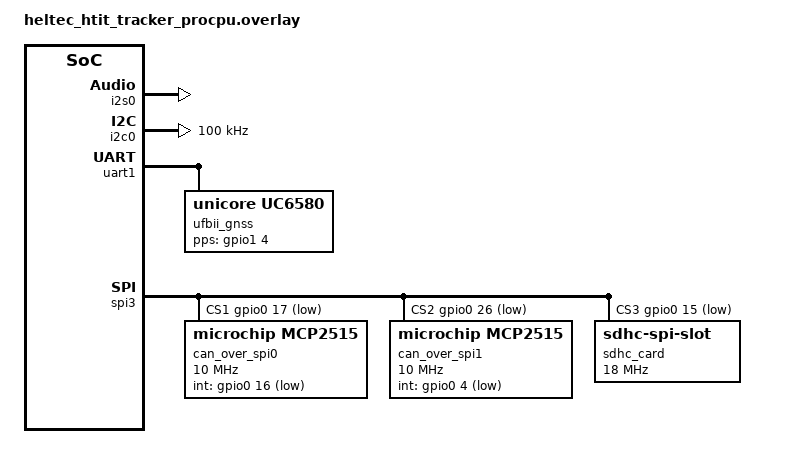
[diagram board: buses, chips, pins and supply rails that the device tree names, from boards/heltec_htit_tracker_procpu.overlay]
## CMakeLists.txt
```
cmake_minimum_required(VERSION 3.20.0)
find_package(Zephyr REQUIRED HINTS $ENV{ZEPHYR_BASE})

project(hyundai-remote)

target_sources(app PRIVATE 
    src/main.c
    src/built-in-test.c
    src/roles.c
    src/sys/storage.c
    src/sys/audio.c
    src/sys/nrvc2_can.c
    src/sys/comms.c
)

target_include_directories(app PRIVATE
    nrvc2_security/include
    ../include/nrvc2
)

target_link_libraries(app PRIVATE 
    nrvc2_security
)
```

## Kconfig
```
config DEVICE_ROLE
    int "DEVICE_ROLE | 1: FOB, 2: TRC"
    range 1 2
    default 1 if CONFIG_BOARD_HELTEC_WIFI_LORA32_v3
    default 2 if CONFIG_BOARD_HELTEC_HTIT_TRACKER
    help
        Set device role, 1: fob-commander-transmitter, 2: tracker-controller-transponder

menu "Installed Devices"
    config EN_GPIO_LED0
        bool "LED0 Installed"
        default y
        help
            Enable if LED 0 is installed.

    config EN_GPIO_SW0
        bool "SW0 Installed"
        default y
        help
            Enable if Switch 0 is installed.

    config EN_DEV_LORA
        bool "LORA Installed"
        default y
        help
            Enable if LoRa transmitter is installed. 

    config EN_DEV_DISPLAY
        bool "Display Installed"
        default y
        help
            Enable if Display is installed. On TRC this enables backlight as well.
    
    config EN_DEV_SDHC
        bool "SD Card Installed"
        default y
        help
            Enable if SD Card/Reader is installed.
    
    if DEVICE_ROLE = 2 
        config EN_DEV_I2S
            bool "I2S Amp Installed"
            default y
            help
                Enable if I2S Amplifier is installed.

        config EN_DEV_UFIREBIRDII
            bool "UFirebirdII GNSS Installed"
            default y
            help
                Enable if UFirebirdII GNSS is installed.

        config EN_DEV_CAN0
            bool "CAN XCVR 0 Installed"
            default y
            help
                Enable if CAN transceiver 0 is installed. 
                TODO: When CAN1 added rename them from CANX to which net they are on.
                Ex: CAN0 -> CAN-OBD; CAN1 -> CAN-ECU or something....

        config EN_DEV_CAN1
            bool "CAN XCVR 1 Installed"
            default y
            help
                Enable if CAN transceiver 1 is installed
    endif
endmenu 

menu "Zephyr Kernel"
source "Kconfig.zephyr"
endmenu
```

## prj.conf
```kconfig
# memory
CONFIG_MAIN_STACK_SIZE=4096
CONFIG_SYSTEM_WORKQUEUE_STACK_SIZE=4096

CONFIG_GPIO=y
CONFIG_I2C=y
CONFIG_SPI=y

CONFIG_SERIAL=y
CONFIG_CONSOLE=y
CONFIG_UART_CONSOLE=y
CONFIG_UART_LINE_CTRL=y
CONFIG_UART_INTERRUPT_DRIVEN=y
CONFIG_SHELL=y
# CONFIG_CONSOLE_SUBSYS=y
CONFIG_STDOUT_CONSOLE=y
CONFIG_LOG=y
# CONFIG_LOG_BUFFER_SIZE=8192 # depends on deferred logging
CONFIG_PRINTK=y
CONFIG_LOG_PRINTK=y

# display and lvgl
CONFIG_DISPLAY=y
# CONFIG_LVGL=y
# CONFIG_LV_USE_LABEL=y
# CONFIG_LV_USE_ARC=y
# CONFIG_LV_FONT_MONTSERRAT_14=y
# CONFIG_LV_Z_MEM_POOL_SIZE=250000

# sd card reqs
CONFIG_DISK_DRIVERS=y
CONFIG_DISK_ACCESS=y
CONFIG_FILE_SYSTEM=y
CONFIG_SDMMC_SUBSYS=y
CONFIG_DISK_DRIVER_SDMMC=y
CONFIG_FAT_FILESYSTEM_ELM=y
CONFIG_SD_LOG_LEVEL_WRN=y
CONFIG_FS_FATFS_LFN=y # large filenames >14 chars

# I2S audio reqs
CONFIG_I2S=y

# lora reqs
CONFIG_LORA=y

# kernel extras
CONFIG_KERNEL_SHELL=y
CONFIG_REBOOT=y

# disable outside of debugging
# CONFIG_LV_USE_LOG=y
CONFIG_LOG_MODE_IMMEDIATE=y
# CONFIG_STACK_SENTINEL=y
```

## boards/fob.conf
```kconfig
# devices
CONFIG_EN_GPIO_LED0=y
CONFIG_EN_GPIO_SW0=y
CONFIG_EN_DEV_LORA=y
CONFIG_EN_DEV_DISPLAY=y
CONFIG_EN_DEV_SDHC=y
# TODO: add i2s
```

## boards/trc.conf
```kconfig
# devices
CONFIG_EN_GPIO_LED0=y
CONFIG_EN_GPIO_SW0=y
CONFIG_EN_DEV_LORA=y
CONFIG_EN_DEV_DISPLAY=y
CONFIG_EN_DEV_SDHC=y
CONFIG_EN_DEV_I2S=y
CONFIG_EN_DEV_UFIREBIRDII=y

# ufirebirdii reqs
CONFIG_UFIREBIRDII=y
CONFIG_UC6580=y
CONFIG_SYSTEM_WORKQUEUE_STACK_SIZE=2048
CONFIG_PICOLIBC_IO_FLOAT=y

# CAN reqs
CONFIG_CAN=y
CONFIG_CAN_SHELL=y
CONFIG_CAN_MCP2515=y

# CAN Not ready as I need proper CANFD modules
CONFIG_EN_DEV_CAN0=n
CONFIG_EN_DEV_CAN1=n

# MDR I2C Testing
CONFIG_I2C=y
CONFIG_SHELL=y
CONFIG_I2C_SHELL=y
```

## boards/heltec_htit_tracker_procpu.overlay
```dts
/ {
    aliases {
        can0 = &can_over_spi0;
        can1 = &can_over_spi1;
        sdhc0 = &sdhc_card;
        i2s-tx = &i2s0;
        ufirebirdii = &ufbii_gnss;
    };

    chosen {
        zephyr,canbus = &can_over_spi0;
    };
};

&pinctrl {
    i2s_default: i2s_default {
        group1 {
            pinmux = <I2S0_O_WS_GPIO7>, // set output WS pin (LRC)
                    <I2S0_O_BCK_GPIO6>, // set outpit BCK pin (BCLK)
                    <I2S0_O_SD_GPIO5>; // serial data, not mode select (DIN)
        };
    };

    i2c0_default: i2c0_default {
        group1 {
            pinmux = <I2C0_SDA_GPIO45>, // MDA SDA
                <I2C0_SCL_GPIO46>;      // MDA SCL
            drive-open-drain;
            bias-pull-up;
        };
    };
};

&i2s0 {
    status = "okay";
    pinctrl-0 = <&i2s_default>;
    pinctrl-names = "default";

    dmas = <&dma 3>;
    dma-names = "tx";
};

&dma {
    status = "okay";
};

&i2c0 {
    status = "okay";
    pinctrl-0 = <&i2c0_default>;
    pinctrl-names = "default";
    clock-frequency = <I2C_BITRATE_STANDARD>; // increase later if needed
};

&uart1 {
    ufbii_gnss: uc6580 {
        compatible = "unicore,uc6580";
        status = "okay";
        pps-gpios = <&gpio1 4 GPIO_ACTIVE_HIGH>; // GPIO 36 == GPIO1 4
    };
};

&spi3 {
    cs-gpios = <&gpio0 8 GPIO_ACTIVE_LOW>,  // preexisting lora cs
            <&gpio0 17 GPIO_ACTIVE_LOW>,    // CAN module 0
            <&gpio0 26 GPIO_ACTIVE_LOW>,    // CAN module 1
            <&gpio0 15 GPIO_ACTIVE_LOW>;    // SD card

    can_over_spi0: can@1 {
        compatible = "microchip,mcp2515";
        reg = <1>;
        status = "okay";
        osc-freq = <DT_FREQ_M(16)>;
        int-gpios = <&gpio0 16 GPIO_ACTIVE_LOW>;
        spi-max-frequency = <DT_FREQ_M(10)>;
    };

    can_over_spi1: can@2 {
        compatible = "microchip,mcp2515";
        reg = <2>;
        status = "okay";
        osc-freq = <DT_FREQ_M(16)>;
        int-gpios = <&gpio0 4 GPIO_ACTIVE_LOW>;
        spi-max-frequency = <DT_FREQ_M(10)>;
    };

    sdhc_card: sdhc@3 {
        compatible = "zephyr,sdhc-spi-slot";
        reg = <3>;
        status = "okay";
        mmc {
            compatible = "zephyr,sdmmc-disk";
            disk-name = "SD";
            status = "okay";
        };
        spi-max-frequency = <DT_FREQ_M(18)>;
    };
};
```

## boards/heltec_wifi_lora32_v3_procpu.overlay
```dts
/ {
    aliases {
    };

    chosen {
    };
};

&pinctrl {
    spim3_default: spim3_default {
		group1 {
			pinmux = <SPIM3_MISO_GPIO41>,
				 <SPIM3_SCLK_GPIO39>;
		};
		group2 {
			pinmux = <SPIM3_MOSI_GPIO40>;
			output-low;
		};
	};
};

&spi3 {
    #address-cells = <1>;
    #size-cells = <0>;
    status = "okay";
    pinctrl-0 = <&spim3_default>;
    pinctrl-names = "default";
    cs-gpios = <&gpio1 10 GPIO_ACTIVE_LOW>; // SD card GPIO 42 == GPIO1 10

    sdhc_card: sdhc@0 {
        compatible = "zephyr,sdhc-spi-slot";
        reg = <0>;
        status = "okay";
        mmc {
            compatible = "zephyr,sdmmc-disk";
            disk-name = "SD";
            status = "okay";
        };
        spi-max-frequency = <DT_FREQ_M(18)>;
    };
};
```

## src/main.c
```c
#include <stdio.h>
#include <zephyr/logging/log.h>
#include <zephyr/kernel.h>

#include <nrvc2_security.h>
#include <nrvc2_errno.h>

#include "built-in-test.h"
#include "roles.h"

LOG_MODULE_REGISTER(main);

int main(void) {
    printk("Waking up...\n\n");
    
    k_msleep(2 * 1000);

    bool configured = role_config();
    if (!configured) {
        LOG_ERR("ROLE CFG FAIL");
    }
    
    bit_basic();

    // comms test
    const char pt[] = "The quick brown fox jumped over the lazy dog!\n";
    uint8_t ct[sizeof(pt)];
    uint8_t pt_out[sizeof(pt)];
    const keyopt_t keyopt = NRVC2_KEYOPT_SESS_COMMS_TRC2FOB;
    uint8_t tag[NRVC2_SECURITY_TAG_SIZE];

    // encryption test
    int ret = nrvc2_security_encrypt_and_sign(keyopt, pt, sizeof(pt), ct, tag);
    printk("encrypt and sign 1 returns %d\n", ret);

    printk("sign 1: 0x");
    for (uint8_t* tb = tag; tb < tag + sizeof(tag); tb++)
        printk("%02x", *tb);
    printk("\n");

    printk("ct 1: 0x");
    for (uint8_t* cb = ct; cb < ct + sizeof(ct); cb++)
        printk("%02x", *cb);
    printk("\n");

    // decryption test
    int seqn = 0;
    ret = nrvc2_security_decrypt_and_verify(keyopt, ct, sizeof(ct), seqn, tag, pt_out);
    if (ret == -EAUTH)
        printk("Auth error!\n");
    if (ret == -ESEQUENCE)
        printk("Sequence number error!\n");

    
    printk("pt: '");
    for (char* c = pt_out; c < pt_out + sizeof(pt_out); c++)
        printk("%c", *c);
    printk("'\n");

    return 0;
}
```

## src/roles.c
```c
#include "roles.h"

#include <zephyr/logging/log.h>
#include <zephyr/fs/fs.h>
#include <zephyr/storage/disk_access.h>
#include <zephyr/drivers/display.h>
#include <zephyr/shell/shell.h>
#include <nrvc2_security.h>

#include "sys/nrvc2_can.h"
#include "sys/comms.h"

const char *FOB_STR = "FOB-COMMANDER-XMTR";
const char *TRC_STR = "TRACK-CONTROL-XPDR";

#if CONFIG_EN_GPIO_LED0
#define LED0_NODE DT_ALIAS(led0)
const struct gpio_dt_spec led0 = GPIO_DT_SPEC_GET(LED0_NODE, gpios);
#endif

#if CONFIG_EN_GPIO_SW0
#define SW0_NODE DT_ALIAS(sw0)
const struct gpio_dt_spec sw0 = GPIO_DT_SPEC_GET(SW0_NODE, gpios);
#endif

#if CONFIG_EN_DEV_LORA
#define LORA_NODE DT_NODELABEL(lora0)
const struct device * const lora = DEVICE_DT_GET(LORA_NODE);
#endif

#if defined(CONFIG_DEVICE_ROLE) && (CONFIG_DEVICE_ROLE == DEF_ROLE_FOB)

#if CONFIG_EN_DEV_DISPLAY
#define DISPLAY_NODE DT_CHOSEN(zephyr_display)
const struct device * const display = DEVICE_DT_GET(DISPLAY_NODE);
#endif

static role_devs_t m_role_devs_fob = {
#if CONFIG_EN_GPIO_LED0
    .gpio_led0 = &led0,
    .gpio_led0_stat = DEVSTAT_NOT_RDY,
#else
    .gpio_led0 = NULL,
    .gpio_led0_stat = DEVSTAT_NOTINSTALLED,
#endif

#if CONFIG_EN_GPIO_SW0
    .gpio_sw0 = &sw0,
    .gpio_sw0_stat = DEVSTAT_NOT_RDY,
#else
    .gpio_sw0 = &sw0,
    .gpio_sw0_stat = DEVSTAT_NOTINSTALLED,
#endif

#if CONFIG_EN_DEV_LORA
    .dev_lora = lora,
    .dev_lora_stat = DEVSTAT_NOT_RDY,
#else
    .dev_lora = NULL,
    .dev_lora_stat = DEVSTAT_NOTINSTALLED,
#endif

#if CONFIG_EN_DEV_DISPLAY
    .dev_display = display,
    .gpio_blight = NULL,
    .dev_display_stat = DEVSTAT_NOT_RDY,
    .gpio_blight_stat = DEVSTAT_NOTINSTALLED,
#else
    .dev_display = NULL,
    .gpio_blight = NULL,
    .dev_display_stat = DEVSTAT_NOTINSTALLED,
    .gpio_blight_stat = DEVSTAT_NOTINSTALLED,
#endif

    .dev_can0 = NULL,
    .dev_can0_stat  = DEVSTAT_NOTINSTALLED,

    .dev_can1 = NULL,
    .dev_can1_stat = DEVSTAT_NOTINSTALLED,

    .dev_i2s = NULL,
    .dev_i2s_stat = DEVSTAT_NOTINSTALLED,

    .dev_ufirebirdii = NULL,
    .dev_ufirebirdii_stat = DEVSTAT_NOTINSTALLED,

#if CONFIG_EN_DEV_SDHC
    .dev_sdcard_stat = DEVSTAT_NOT_RDY,
#else
    .dev_sdcard_stat = DEVSTAT_NOTINSTALLED
#endif
};
role_devs_t* role_devs = &m_role_devs_fob;

#elif defined(CONFIG_DEVICE_ROLE) && (CONFIG_DEVICE_ROLE == DEF_ROLE_TRC)

#if CONFIG_EN_DEV_DISPLAY
#define DISPLAY_NODE DT_CHOSEN(zephyr_display)
const struct device * const display = DEVICE_DT_GET(DISPLAY_NODE);
#define BLIGHT_NODE DT_ALIAS(blight)
const struct gpio_dt_spec blight = GPIO_DT_SPEC_GET(BLIGHT_NODE, gpios);
#endif

#if CONFIG_EN_DEV_I2S
#define I2S_NODE DT_ALIAS(i2s_tx)
const struct device * const i2s = DEVICE_DT_GET(I2S_NODE);
#endif

#if CONFIG_EN_DEV_UFIREBIRDII
#define UFIREBIRDII_NODE DT_ALIAS(ufirebirdii)
const struct device * const ufirebirdii = DEVICE_DT_GET(UFIREBIRDII_NODE);
#endif

#if CONFIG_EN_DEV_CAN0
#define CAN0_NODE DT_ALIAS(can0) 
const struct device * const can0 = DEVICE_DT_GET(CAN0_NODE);
#endif

#if CONFIG_EN_DEV_CAN1
#define CAN1_NODE DT_ALIAS(can1)
const struct device * const can1 = DEVICE_DT_GET(CAN1_NODE);
#endif

static role_devs_t m_role_devs_trc = {
#if CONFIG_EN_GPIO_LED0
    .gpio_led0 = &led0,
    .gpio_led0_stat = DEVSTAT_NOT_RDY,
#else
    .gpio_led0 = NULL,
    .gpio_led0_stat = DEVSTAT_NOTINSTALLED,
#endif

#if CONFIG_EN_GPIO_SW0
    .gpio_sw0 = &sw0,
    .gpio_sw0_stat = DEVSTAT_NOT_RDY,
#else
    .gpio_sw0 = &sw0,
    .gpio_sw0_stat = DEVSTAT_NOTINSTALLED,
#endif

#if CONFIG_EN_DEV_LORA
    .dev_lora = lora,
    .dev_lora_stat = DEVSTAT_NOT_RDY,
#else
    .dev_lora = NULL,
    .dev_lora_stat = DEVSTAT_NOTINSTALLED,
#endif

#if CONFIG_EN_DEV_DISPLAY
    .dev_display = display,
    .gpio_blight = &blight,
    .dev_display_stat = DEVSTAT_NOT_RDY,
    .gpio_blight_stat = DEVSTAT_NOT_RDY,
#else
    .dev_display = NULL,
    .gpio_blight = NULL,
    .dev_display_stat = DEVSTAT_NOTINSTALLED,
    .gpio_blight_stat = DEVSTAT_NOTINSTALLED,
#endif

#if CONFIG_EN_DEV_CAN0
    .dev_can0 = can0,
    .dev_can0_stat = DEVSTAT_NOT_RDY,
#else
    .dev_can0 = NULL,
    .dev_can0_stat  = DEVSTAT_NOTINSTALLED,
#endif

#if CONFIG_EN_DEV_CAN1
    .dev_can1 = can1,
    .dev_can1_stat = DEVSTAT_NOT_RDY,
#else
    .dev_can0 = NULL,
    .dev_can0_stat  = DEVSTAT_NOTINSTALLED,
#endif

#if CONFIG_EN_DEV_I2S
    .dev_i2s = i2s,
    .dev_i2s_stat = DEVSTAT_NOT_RDY,
#else
    .dev_i2s = NULL,
    .dev_i2s_stat = DEVSTAT_NOTINSTALLED,
#endif

#if CONFIG_EN_DEV_UFIREBIRDII
    .dev_ufirebirdii = ufirebirdii,
    .dev_ufirebirdii_stat = DEVSTAT_NOT_RDY,
#else
    .dev_ufirebirdii = NULL,
    .dev_ufirebirdii_stat = DEVSTAT_NOTINSTALLED,
#endif

#if CONFIG_EN_DEV_SDHC
    .dev_sdcard_stat = DEVSTAT_NOT_RDY
#else
    .dev_sdcard_stat = DEVSTAT_NOTINSTALLED
#endif
};
role_devs_t* role_devs = &m_role_devs_trc;

#endif

LOG_MODULE_REGISTER(roles, LOG_LEVEL_DBG);

static bool init_common()
{ 
    const char *HASHES = "################################";
    printk("%s\n", HASHES);
    printk("#           CFG INIT           #\n");
    printk("%s\n", HASHES);

    bool rdy = true;

    // LED0
    if (role_devs->gpio_led0_stat == DEVSTAT_NOTINSTALLED)
        LOG_INF("LED0\t\tNOT INSTALLED");
    else if (!device_is_ready(role_devs->gpio_led0->port)) {
        LOG_ERR("LED device is not ready");
        role_devs->gpio_led0_stat = DEVSTAT_ERR;
        rdy = false;
    } else {
        role_devs->gpio_led0_stat = DEVSTAT_RDY;
        LOG_INF("LED0\t\tRDY");
    }
    
    // SW0
    if (role_devs->gpio_sw0_stat == DEVSTAT_NOTINSTALLED)
        LOG_INF("SW0\t\tNOT INSTALLED");
    if (!device_is_ready(role_devs->gpio_sw0->port)) {
        LOG_ERR("User switch device is not ready");
        role_devs->gpio_sw0_stat = DEVSTAT_ERR;
        rdy = false;
    } else {
        role_devs->gpio_sw0_stat = DEVSTAT_RDY;
        LOG_INF("SW0\t\tRDY");
    }
    
    // LORA
    if (role_devs->dev_lora_stat == DEVSTAT_NOTINSTALLED)
        LOG_INF("LORA\t\tNOT INSTALLED");
    else if (!device_is_ready(role_devs->dev_lora)) {
        LOG_ERR("LoRa device is not ready");
        role_devs->dev_lora_stat = DEVSTAT_ERR;
        rdy = false;
    } else {
        role_devs->dev_lora_stat = DEVSTAT_RDY;
        LOG_INF("LORA\t\tRDY");
    }

    // Display
    if (role_devs->dev_display_stat == DEVSTAT_NOTINSTALLED)
        LOG_INF("DISPLAY\t\tNOT INSTALLED");
    else if (!device_is_ready(role_devs->dev_display)) {
        LOG_ERR("Display device is not ready");
        role_devs->dev_display_stat = DEVSTAT_ERR;
        rdy = false;
    } else {
        role_devs->dev_display_stat = DEVSTAT_RDY;
        LOG_INF("DISPLAY\t\tRDY");

        // clear display
        int ret = display_blanking_on(role_devs->dev_display);
        if (ret < 0) {
            LOG_ERR("Display blanking on failed: %d", ret);
            role_devs->dev_display_stat = DEVSTAT_ERR;
            rdy = false;
        }
    }

    // SDHC
    if (role_devs->dev_sdcard_stat == DEVSTAT_NOTINSTALLED) 
        LOG_INF("SDHC\t\tNOT INSTALLED");
    else {
        do {
            const char* disk_pdrv = "SD";

            int ret = disk_access_ioctl(disk_pdrv, DISK_IOCTL_CTRL_INIT, NULL);

            if (ret < 0) {
                LOG_ERR("SD card init failed: storage init error %d", ret);
                role_devs->dev_sdcard_stat = DEVSTAT_ERR;
                rdy = false;
                break;
            }

            k_msleep(2);

            ret = disk_access_ioctl(disk_pdrv, DISK_IOCTL_CTRL_DEINIT, NULL);
            if (ret < 0) {
                LOG_ERR("SD card init failed: storage deinit error %d", ret);
                role_devs->dev_sdcard_stat = DEVSTAT_ERR;
                rdy = false;
                break;
            }

            role_devs->dev_sdcard_stat = DEVSTAT_RDY;  
            LOG_INF("SDHC\t\tRDY");
        } while (false);
    }

    // Systems
    // Security
    {
        int ret = nrvc2_security_init();
        if (ret < 0) {
            LOG_ERR("Security init failed: %d", ret);
            rdy = false;
        }

        LOG_INF("SECURITY\tRDY");
    }

    // Comms
    // requires lora to be ready to configure modem
    if (role_devs->dev_lora_stat != DEVSTAT_RDY)
        LOG_INF("COMMS\t\tDISABLED");
    else {
        int ret = comms_init();
        
        if (ret < 0) {
            LOG_ERR("Comms init failed: %d", ret);
            rdy = false;
            LOG_INF("COMMS\t\tRDY");
        }
    }

    // CAN
    {
        int ret = can_init();
        if (ret< 0) {
            LOG_ERR("CAN init failed: %d", ret);
            rdy = false;
        }

        LOG_INF("CAN\t\tRDY");
    }

    return rdy;
}

#if defined(CONFIG_DEVICE_ROLE) && (CONFIG_DEVICE_ROLE == DEF_ROLE_FOB)
static bool init_fob() {
    return true;
}

#elif defined(CONFIG_DEVICE_ROLE) && (CONFIG_DEVICE_ROLE == DEF_ROLE_TRC)

static bool init_trc_i2s() {
    if (role_devs->dev_i2s_stat == DEVSTAT_NOTINSTALLED) {
        LOG_INF("I2S\t\tNOT INSTALLED");
        return true;
    }

    int ret = device_is_ready(role_devs->dev_i2s);
    if (ret < 0) {
        LOG_ERR("I2S device is not ready");
        role_devs->dev_i2s_stat = DEVSTAT_ERR;
        return false;
    }

    role_devs->dev_i2s_stat = DEVSTAT_RDY;
    LOG_INF("I2S\t\tRDY");
    return true;
}

static bool init_trc_ufirebirdii() {
    if (role_devs->dev_ufirebirdii_stat == DEVSTAT_NOTINSTALLED) {
        LOG_INF("UFirebirdII\tNOT INSTALLED");
        return true;
    }

    int ret = device_is_ready(role_devs->dev_ufirebirdii);
    if (ret < 0) {
        LOG_ERR("UFirebirdII device is not ready");
        role_devs->dev_ufirebirdii_stat = DEVSTAT_ERR;
        return false;
    }

    role_devs->dev_ufirebirdii_stat = DEVSTAT_RDY;
    LOG_INF("UFirebirdII\tRDY");
    
    return true;
}

static bool init_trc_can0() {
    if (role_devs->dev_can0_stat == DEVSTAT_NOTINSTALLED) {
        LOG_INF("CAN0\t\tNOT INSTALLED");
        return true;
    }
    
    int ret = device_is_ready(role_devs->dev_can0);
    if (ret < 0) {
        LOG_ERR("CAN device is not ready");
        role_devs->dev_can0_stat = DEVSTAT_ERR;
        return false;
    }

    ret = can_dev_init(role_devs->dev_can0, "CAN0");
    if (ret < 0) {
        role_devs->dev_can0_stat = DEVSTAT_ERR;        
        return false;
    }

    role_devs->dev_can0_stat = DEVSTAT_RDY;
    LOG_INF("CAN0\t\tRDY");

    return true;
}

static bool init_trc_can1() {
    if (role_devs->dev_can1_stat == DEVSTAT_NOTINSTALLED) {
        LOG_INF("CAN1\t\tNOT INSTALLED");
        return true;
    }

    int ret = device_is_ready(role_devs->dev_can1);
    if (ret < 0) {
        LOG_ERR("CAN1 device is not ready");
        role_devs->dev_can1_stat = DEVSTAT_ERR;
        return false;
    }

    ret = can_dev_init(role_devs->dev_can1, "CAN1");
    if (ret < 0) {
        role_devs->dev_can1_stat = DEVSTAT_ERR;        
        return false;
    }

    role_devs->dev_can1_stat = DEVSTAT_RDY;
    LOG_INF("CAN1\t\tRDY");
    
    return true;
}

static bool init_trc() {
    bool rdy = true;

    if (role_devs->dev_display_stat == DEVSTAT_RDY && !device_is_ready(role_devs->gpio_blight->port)) {
        LOG_ERR("TRC Backlight GPIO Dev not ready.");
        role_devs->dev_display_stat = DEVSTAT_NOT_RDY;
        role_devs->gpio_blight_stat = DEVSTAT_ERR;
        rdy = false;
    } else 
        role_devs->gpio_blight_stat = DEVSTAT_RDY;

    rdy &= init_trc_i2s();

    rdy &= init_trc_ufirebirdii();

    rdy &= init_trc_can0();
    rdy &= init_trc_can1();

    return rdy;
}

#endif

bool role_config()
{
    // config common
    bool success = true;

    success &= init_common();
    if (!success)
        LOG_ERR("Role init common failed.");

    dev_role role = role_get();

    switch (role)
    {
    case ROLE_FOB:
#if defined(CONFIG_DEVICE_ROLE) && (CONFIG_DEVICE_ROLE == DEF_ROLE_FOB)
        success &= init_fob();
#endif
        break;
    case ROLE_TRC:
#if defined(CONFIG_DEVICE_ROLE) && (CONFIG_DEVICE_ROLE == DEF_ROLE_TRC)
        success &= init_trc();
#endif
        break;
    case ROLE_UKN:
    default:
        LOG_ERR("Role init failed: Unknown role.");
        return false;
    }

    LOG_INF("Role %s configuration %s.", role_tostring(), success ? "complete" : "incomplete");
    return success;
}

static const char* devstat_to_str(devstat_t s) {
    switch (s) {
        case DEVSTAT_NOTINSTALLED: return "NOT INSTALLED";
        case DEVSTAT_NOT_RDY: return "NOT RDY";
        case DEVSTAT_RDY: return "RDY";
        case DEVSTAT_ERR: return "ERR";
        default: return "UNKNOWN";
    }
}

static int shell_role_status(const struct shell *shell, size_t argc, char **argv) {
    (void)shell; (void)argc; (void)argv;

    LOG_INF("--- Device status ---");
    LOG_INF("LED0\t\t%s", devstat_to_str(role_devs->gpio_led0_stat));
    LOG_INF("SW0\t\t%s", devstat_to_str(role_devs->gpio_sw0_stat));
    LOG_INF("LORA\t\t%s", devstat_to_str(role_devs->dev_lora_stat));
    LOG_INF("DISPLAY\t\t%s", devstat_to_str(role_devs->dev_display_stat));
    LOG_INF("BLIGHT\t\t%s", devstat_to_str(role_devs->gpio_blight_stat));
    LOG_INF("CAN0\t\t%s", devstat_to_str(role_devs->dev_can0_stat));
    LOG_INF("CAN1\t\t%s", devstat_to_str(role_devs->dev_can1_stat));
    LOG_INF("I2S\t\t%s", devstat_to_str(role_devs->dev_i2s_stat));
    LOG_INF("UFBII\t\t%s", devstat_to_str(role_devs->dev_ufirebirdii_stat));
    LOG_INF("SDHC\t\t%s", devstat_to_str(role_devs->dev_sdcard_stat));

    LOG_INF("--- Systems status ---");
    LOG_INF("SECURITY\t%s", nrvc2_security_rdy() ? "RDY" : "NOT RDY");
    LOG_INF("COMMS\t\t%s", comms_rdy() ? "RDY" : "NOT RDY");

    return 0;
}

SHELL_STATIC_SUBCMD_SET_CREATE(sub_role,
    SHELL_CMD(status, NULL, "Print device status", shell_role_status),
    SHELL_SUBCMD_SET_END
);

SHELL_CMD_REGISTER(role, &sub_role, "Role utilities", NULL);
```

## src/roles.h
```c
/// Provides devices and role management

#ifndef ROLES_H
#define ROLES_H

#include <stdbool.h>

#include <zephyr/kernel.h>
#include <zephyr/drivers/gpio.h>
#include <zephyr/linker/linker-defs.h>

extern const char* FOB_STR;
extern const char* TRC_STR;

#define DEF_ROLE_FOB 1
#define DEF_ROLE_TRC 2
#define DEF_ROLE_UKN 0

#define DEF_ROLE_IS_TRC (defined(CONFIG_DEVICE_ROLE) && (CONFIG_DEVICE_ROLE == DEF_ROLE_TRC))
#define ROLE_IS_FOB (role_get() == ROLE_FOB)
#define ROLE_IS_TRC (role_get() == ROLE_TRC)

typedef enum {
   DEVSTAT_NOTINSTALLED = 0,
   DEVSTAT_NOT_RDY,
   DEVSTAT_RDY,
   DEVSTAT_ERR
} devstat_t;

typedef struct  {
   const struct gpio_dt_spec *gpio_led0;
   devstat_t gpio_led0_stat;

   const struct gpio_dt_spec *gpio_sw0;
   devstat_t gpio_sw0_stat;

   const struct device *dev_lora;
   devstat_t dev_lora_stat;

   const struct device *dev_display;
   const struct gpio_dt_spec *gpio_blight;
   devstat_t dev_display_stat;
   devstat_t gpio_blight_stat;

   const struct device *dev_can0;
   devstat_t dev_can0_stat;

   const struct device *dev_can1;
   devstat_t dev_can1_stat;

   const struct device *dev_i2s;
   devstat_t dev_i2s_stat;

   const struct device *dev_ufirebirdii;
   devstat_t dev_ufirebirdii_stat;

   devstat_t dev_sdcard_stat;
} role_devs_t;

extern role_devs_t* role_devs;

#if defined(CONFIG_DEVICE_ROLE) && (CONFIG_DEVICE_ROLE == DEF_ROLE_FOB)
#define LORA_MAX_POW_DBM 19 // up to 21±1

#elif defined(CONFIG_DEVICE_ROLE) && (CONFIG_DEVICE_ROLE == DEF_ROLE_TRC)
#define LORA_MAX_POW_DBM 19 // up to 21±1

#endif
#define LORA_DEFAULT_SF SF_8
#define LORA_DEFAULT_PREAMBLE_LEN 18

typedef enum {
   ROLE_FOB = DEF_ROLE_FOB,
   ROLE_TRC = DEF_ROLE_TRC,
   ROLE_UKN = DEF_ROLE_UKN
} dev_role;

inline const dev_role role_get() {
#if defined(CONFIG_DEVICE_ROLE) && (CONFIG_DEVICE_ROLE == DEF_ROLE_FOB)
   return ROLE_FOB;
#elif defined(CONFIG_DEVICE_ROLE) && (CONFIG_DEVICE_ROLE == DEF_ROLE_TRC)
   return ROLE_TRC;
#else
   return ROLE_UKN;
#endif
}

inline const char* role_tostring() {
   dev_role role = role_get();

   switch (role) {
      case ROLE_FOB:
         return FOB_STR;
      case ROLE_TRC:
         return TRC_STR;
      case ROLE_UKN:
      default:
         return "UNKNOWN";
   }
}

/**
 * Automatically get device role and configure GPIOs
 */
bool role_config();

#endif // ROLES_H
```
